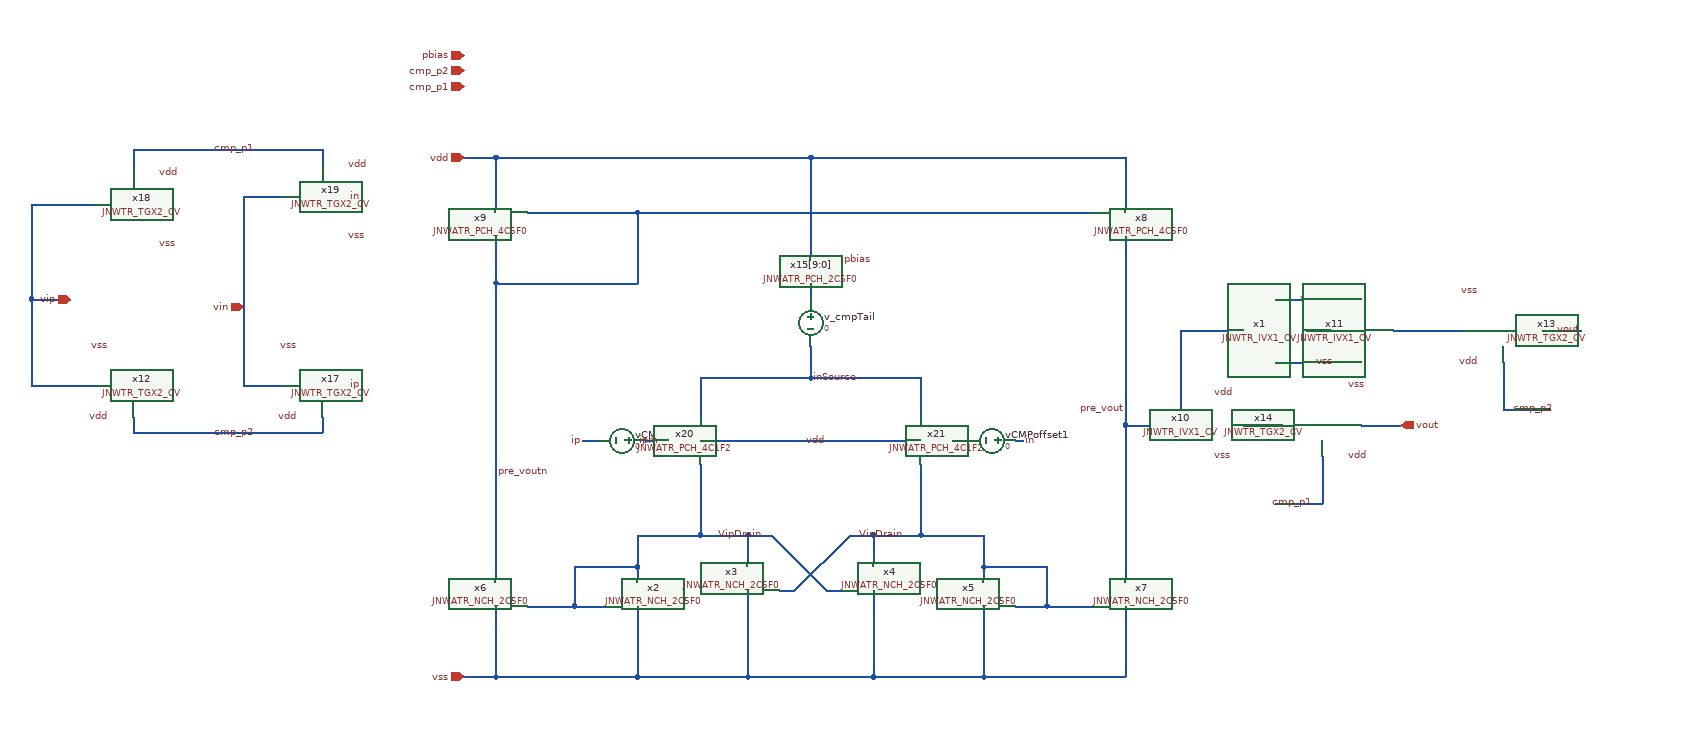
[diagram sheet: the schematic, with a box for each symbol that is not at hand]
v {xschem version=3.4.6 file_version=1.2}
G {}
K {}
V {}
S {}
E {}
N 540 -430 540 -340 {
lab=VipDrain}
N 460 -340 460 -300 {
lab=VipDrain}
N 460 -340 540 -340 {
lab=VipDrain}
N 540 -340 600 -340 {
lab=VipDrain}
N 600 -340 600 -300 {
lab=VipDrain}
N 820 -430 820 -340 {
lab=VinDrain}
N 760 -340 760 -300 {
lab=VinDrain}
N 760 -340 820 -340 {
lab=VinDrain}
N 820 -340 900 -340 {
lab=VinDrain}
N 900 -300 900 -280 {
lab=VinDrain}
N 640 -270 660 -270 {
lab=VinDrain}
N 660 -270 730 -340 {
lab=VinDrain}
N 700 -270 720 -270 {
lab=VipDrain}
N 630 -340 700 -270 {
lab=VipDrain}
N 600 -340 630 -340 {
lab=VipDrain}
N 730 -340 760 -340 {
lab=VinDrain}
N 600 -270 600 -160 {
lab=vss}
N 760 -270 760 -160 {
lab=vss}
N 900 -160 1080 -160 {
lab=vss}
N 460 -160 600 -160 {
lab=vss}
N 600 -160 760 -160 {
lab=vss}
N 760 -160 900 -160 {
lab=vss}
N 900 -250 900 -160 {
lab=vss}
N 460 -250 460 -160 {
lab=vss}
N 380 -250 420 -250 {
lab=VipDrain}
N 380 -300 460 -300 {
lab=VipDrain}
N 380 -300 380 -250 {
lab=VipDrain}
N 320 -250 380 -250 {
lab=VipDrain}
N 460 -300 460 -280 {
lab=VipDrain}
N 980 -300 980 -250 {
lab=VinDrain}
N 900 -300 980 -300 {
lab=VinDrain}
N 900 -340 900 -300 {
lab=VinDrain}
N 940 -250 980 -250 {
lab=VinDrain}
N 280 -250 280 -160 {
lab=vss}
N 1080 -250 1080 -160 {
lab=vss}
N 1080 -480 1080 -280 {
lab=pre_vout}
N 980 -250 1040 -250 {
lab=VinDrain}
N 460 -750 460 -660 {
lab=pre_voutn}
N 320 -750 460 -750 {
lab=pre_voutn}
N 280 -820 280 -750 {
lab=vdd}
N 1080 -820 1080 -750 {
lab=vdd}
N 240 -820 280 -820 {
lab=vdd}
N 280 -160 460 -160 {
lab=vss}
N 240 -160 280 -160 {
lab=vss}
N 1080 -480 1150 -480 {
lab=pre_vout}
N 540 -540 540 -490 {
lab=inSource}
N 820 -540 820 -490 {
lab=inSource}
N 540 -460 820 -460 {
lab=vdd}
N 680 -540 820 -540 {
lab=inSource}
N 680 -820 1080 -820 {
lab=vdd}
N 280 -660 460 -660 {
lab=pre_voutn}
N 280 -720 280 -660 {
lab=pre_voutn}
N 460 -750 1040 -750 {
lab=pre_voutn}
N 1080 -720 1080 -480 {
lab=pre_vout}
N 1230 -480 1280 -480 {
lab=#net1}
N 1330 -440 1330 -380 {
lab=cmp_p1}
N 280 -660 280 -280 {
lab=pre_voutn}
N 1270 -380 1330 -380 {
lab=cmp_p1}
N 1380 -480 1430 -480 {
lab=vout}
N -310 -640 -310 -530 {
lab=vip}
N -310 -760 -230 -760 {
lab=vip}
N -310 -530 -230 -530 {
lab=vip}
N -40 -770 -40 -530 {
lab=vin}
N -40 -770 10 -770 {
lab=vin}
N -40 -530 10 -530 {
lab=vin}
N -180 -490 -180 -470 {
lab=cmp_p2}
N -180 -470 60 -470 {
lab=cmp_p2}
N 60 -490 60 -470 {
lab=cmp_p2}
N -180 -830 -180 -800 {
lab=cmp_p1}
N -180 -830 60 -830 {
lab=cmp_p1}
N 60 -830 60 -810 {
lab=cmp_p1}
N 680 -820 680 -690 {lab=vdd}
N 280 -820 680 -820 {
lab=vdd}
N 680 -580 680 -540 {lab=inSource}
N 540 -540 680 -540 {
lab=inSource}
N 680 -660 680 -640 {lab=#net2}
N 390 -460 410 -460 {lab=ip}
N 470 -460 500 -460 {lab=ipm}
N 1150 -600 1150 -480 {lab=pre_vout}
N 1150 -600 1230 -600 {lab=pre_vout}
N 1270 -560 1380 -560 {lab=vss}
N 1560 -560 1560 -500 {
lab=cmp_p2}
N 1560 -500 1620 -500 {
lab=cmp_p2}
N 1610 -600 1660 -600 {lab=vout}
N 1420 -600 1510 -600 {lab=#net3}
N 1310 -600 1340 -600 {lab=#net4}
N 1270 -640 1380 -640 {lab=vdd}
N -310 -640 -260 -640 {lab=vip}
N -310 -760 -310 -640 {
lab=vip}
N 860 -460 880 -460 {lab=#net5}
N 940 -460 950 -460 {lab=in}
C {devices/ipin.sym} 240 -160 0 0 {name=p2 lab=vss
}
C {devices/ipin.sym} 240 -820 0 0 {name=p3 lab=vdd
}
C {devices/ipin.sym} 240 -950 0 0 {name=p1 lab=pbias
}
C {devices/ipin.sym} -40 -630 0 0 {name=p5 lab=vin
}
C {devices/ipin.sym} -260 -640 0 0 {name=p6 lab=vip
}
C {JNW_ATR_SKY130A/JNWATR_NCH_2C5F0.sym} 420 -250 0 0 {name=x2 }
C {JNW_ATR_SKY130A/JNWATR_NCH_2C5F0.sym} 640 -270 0 1 {name=x3 }
C {JNW_ATR_SKY130A/JNWATR_NCH_2C5F0.sym} 720 -270 0 0 {name=x4 }
C {JNW_ATR_SKY130A/JNWATR_NCH_2C5F0.sym} 940 -250 0 1 {name=x5 }
C {JNW_ATR_SKY130A/JNWATR_NCH_2C5F0.sym} 320 -250 0 1 {name=x6 }
C {JNW_ATR_SKY130A/JNWATR_NCH_2C5F0.sym} 1040 -250 0 0 {name=x7 }
C {JNW_ATR_SKY130A/JNWATR_PCH_4C5F0.sym} 1040 -750 0 0 {name=x8 }
C {JNW_ATR_SKY130A/JNWATR_PCH_4C5F0.sym} 320 -750 0 1 {name=x9 }
C {devices/opin.sym} 1430 -480 0 0 {name=p7 lab=vout}
C {devices/lab_wire.sym} 700 -460 0 0 {name=p4 sig_type=std_logic lab=vdd}
C {JNW_TR_SKY130A/JNWTR_IVX1_CV.sym} 1150 -480 0 0 {name=x10 }
C {devices/ipin.sym} 240 -910 0 0 {name=p10 lab=cmp_p1
}
C {devices/lab_wire.sym} 1300 -640 0 1 {name=p18 sig_type=std_logic lab=vdd}
C {devices/lab_wire.sym} 1190 -440 0 1 {name=p19 sig_type=std_logic lab=vss}
C {JNW_TR_SKY130A/JNWTR_TGX2_CV.sym} 1270 -480 2 1 {name=x14 }
C {devices/lab_wire.sym} 1360 -440 0 1 {name=p20 sig_type=std_logic lab=vdd}
C {devices/lab_wire.sym} 1360 -530 0 1 {name=p21 sig_type=std_logic lab=vss}
C {devices/lab_wire.sym} 1320 -380 0 0 {name=p22 sig_type=std_logic lab=cmp_p1}
C {devices/lab_wire.sym} -130 -530 0 0 {name=p32 sig_type=std_logic lab=in}
C {devices/lab_wire.sym} -130 -760 0 0 {name=p33 sig_type=std_logic lab=ip}
C {devices/lab_wire.sym} 390 -460 0 0 {name=p34 sig_type=std_logic lab=ip}
C {devices/lab_wire.sym} 950 -460 0 1 {name=p35 sig_type=std_logic lab=in}
C {devices/ipin.sym} 240 -930 0 0 {name=p11 lab=cmp_p2
}
C {devices/lab_wire.sym} 800 -340 0 0 {name=p12 sig_type=std_logic lab=VinDrain}
C {devices/lab_wire.sym} 560 -340 0 1 {name=p13 sig_type=std_logic lab=VipDrain}
C {devices/lab_wire.sym} 280 -420 0 1 {name=p37 sig_type=std_logic lab=pre_voutn}
C {devices/lab_wire.sym} 1080 -500 0 0 {name=p38 sig_type=std_logic lab=pre_vout}
C {JNW_TR_SKY130A/JNWTR_TGX2_CV.sym} -120 -530 2 0 {name=x12 }
C {devices/lab_wire.sym} -210 -490 0 0 {name=p29 sig_type=std_logic lab=vdd}
C {devices/lab_wire.sym} -210 -580 0 0 {name=p30 sig_type=std_logic lab=vss}
C {JNW_TR_SKY130A/JNWTR_TGX2_CV.sym} 120 -530 2 0 {name=x17 }
C {devices/lab_wire.sym} 30 -490 0 0 {name=p31 sig_type=std_logic lab=vdd}
C {devices/lab_wire.sym} 30 -580 0 0 {name=p36 sig_type=std_logic lab=vss}
C {JNW_TR_SKY130A/JNWTR_TGX2_CV.sym} -240 -760 0 0 {name=x18 }
C {devices/lab_wire.sym} -150 -800 2 0 {name=p39 sig_type=std_logic lab=vdd}
C {devices/lab_wire.sym} -150 -710 2 0 {name=p40 sig_type=std_logic lab=vss}
C {JNW_TR_SKY130A/JNWTR_TGX2_CV.sym} 0 -770 0 0 {name=x19 }
C {devices/lab_wire.sym} 90 -810 2 0 {name=p41 sig_type=std_logic lab=vdd}
C {devices/lab_wire.sym} 90 -720 2 0 {name=p42 sig_type=std_logic lab=vss}
C {devices/lab_wire.sym} 110 -530 0 0 {name=p43 sig_type=std_logic lab=ip}
C {devices/lab_wire.sym} 110 -770 0 0 {name=p44 sig_type=std_logic lab=in}
C {devices/lab_wire.sym} -80 -470 0 1 {name=p45 sig_type=std_logic lab=cmp_p2}
C {devices/lab_wire.sym} -80 -830 0 1 {name=p46 sig_type=std_logic lab=cmp_p1}
C {devices/lab_wire.sym} 720 -690 0 1 {name=p50 sig_type=std_logic lab=pbias}
C {JNW_ATR_SKY130A/JNWATR_PCH_2C5F0.sym} 720 -690 0 1 {name=x15[9:0]}
C {devices/vsource.sym} 680 -610 0 0 {name=v_cmpTail value=0 savecurrent=true}
C {devices/lab_wire.sym} 680 -540 0 1 {name=p47 sig_type=std_logic lab=inSource}
C {devices/vsource.sym} 440 -460 1 0 {name=vCMPoffset value=0 savecurrent=false}
C {JNW_ATR_SKY130A/JNWATR_PCH_4C1F2.sym} 500 -460 0 0 {name=x20 }
C {JNW_ATR_SKY130A/JNWATR_PCH_4C1F2.sym} 860 -460 0 1 {name=x21 }
C {JNW_TR_SKY130A/JNWTR_IVX1_CV.sym} 1230 -600 0 0 {name=x1 }
C {JNW_TR_SKY130A/JNWTR_IVX1_CV.sym} 1340 -600 0 0 {name=x11 }
C {devices/lab_wire.sym} 1190 -520 0 1 {name=p48 sig_type=std_logic lab=vdd}
C {devices/lab_wire.sym} 1320 -560 0 1 {name=p49 sig_type=std_logic lab=vss}
C {JNW_TR_SKY130A/JNWTR_TGX2_CV.sym} 1620 -600 2 0 {name=x13 }
C {devices/lab_wire.sym} 1530 -560 0 0 {name=p51 sig_type=std_logic lab=vdd}
C {devices/lab_wire.sym} 1530 -650 0 0 {name=p52 sig_type=std_logic lab=vss}
C {devices/lab_wire.sym} 1570 -500 0 1 {name=p53 sig_type=std_logic lab=cmp_p2}
C {devices/lab_wire.sym} 1660 -600 0 0 {name=p54 sig_type=std_logic lab=vout}
C {devices/lab_wire.sym} 490 -460 0 0 {name=p8 sig_type=std_logic lab=ipm}
C {devices/vsource.sym} 910 -460 1 0 {name=vCMPoffset1 value=0 savecurrent=false}
